VERSION 5.7 ;
  NOWIREEXTENSIONATPIN ON ;
  DIVIDERCHAR "/" ;
  BUSBITCHARS "[]" ;
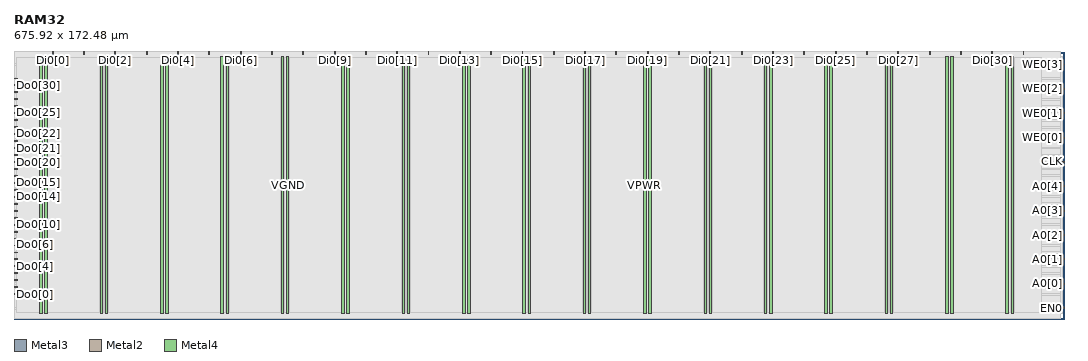
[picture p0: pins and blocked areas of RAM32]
MACRO RAM32
  CLASS BLOCK ;
  FOREIGN RAM32 ;
  ORIGIN 0.000 0.000 ;
  SIZE 675.920 BY 172.480 ;
  PIN A0[0]
    DIRECTION INPUT ;
    USE SIGNAL ;
    ANTENNAGATEAREA 0.726000 ;
    PORT
      LAYER Metal3 ;
        RECT 673.920 22.400 675.920 22.960 ;
    END
  END A0[0]
  PIN A0[1]
    DIRECTION INPUT ;
    USE SIGNAL ;
    ANTENNAGATEAREA 0.726000 ;
    PORT
      LAYER Metal3 ;
        RECT 673.920 38.080 675.920 38.640 ;
    END
  END A0[1]
  PIN A0[2]
    DIRECTION INPUT ;
    USE SIGNAL ;
    ANTENNAGATEAREA 0.726000 ;
    PORT
      LAYER Metal3 ;
        RECT 673.920 53.760 675.920 54.320 ;
    END
  END A0[2]
  PIN A0[3]
    DIRECTION INPUT ;
    USE SIGNAL ;
    ANTENNAGATEAREA 0.726000 ;
    PORT
      LAYER Metal3 ;
        RECT 673.920 69.440 675.920 70.000 ;
    END
  END A0[3]
  PIN A0[4]
    DIRECTION INPUT ;
    USE SIGNAL ;
    ANTENNAGATEAREA 0.726000 ;
    PORT
      LAYER Metal3 ;
        RECT 673.920 85.120 675.920 85.680 ;
    END
  END A0[4]
  PIN CLK
    DIRECTION INPUT ;
    USE SIGNAL ;
    ANTENNAGATEAREA 2.366000 ;
    ANTENNADIFFAREA 0.820800 ;
    PORT
      LAYER Metal3 ;
        RECT 673.920 100.800 675.920 101.360 ;
    END
  END CLK
  PIN Di0[0]
    DIRECTION INPUT ;
    USE SIGNAL ;
    ANTENNAGATEAREA 2.369000 ;
    PORT
      LAYER Metal2 ;
        RECT 24.640 170.480 25.200 172.480 ;
    END
  END Di0[0]
  PIN Di0[10]
    DIRECTION INPUT ;
    USE SIGNAL ;
    ANTENNAGATEAREA 2.369000 ;
    PORT
      LAYER Metal2 ;
        RECT 226.240 170.480 226.800 172.480 ;
    END
  END Di0[10]
  PIN Di0[11]
    DIRECTION INPUT ;
    USE SIGNAL ;
    ANTENNAGATEAREA 2.369000 ;
    PORT
      LAYER Metal2 ;
        RECT 246.400 170.480 246.960 172.480 ;
    END
  END Di0[11]
  PIN Di0[12]
    DIRECTION INPUT ;
    USE SIGNAL ;
    ANTENNAGATEAREA 2.369000 ;
    PORT
      LAYER Metal2 ;
        RECT 266.560 170.480 267.120 172.480 ;
    END
  END Di0[12]
  PIN Di0[13]
    DIRECTION INPUT ;
    USE SIGNAL ;
    ANTENNAGATEAREA 2.369000 ;
    PORT
      LAYER Metal2 ;
        RECT 286.720 170.480 287.280 172.480 ;
    END
  END Di0[13]
  PIN Di0[14]
    DIRECTION INPUT ;
    USE SIGNAL ;
    ANTENNAGATEAREA 2.369000 ;
    PORT
      LAYER Metal2 ;
        RECT 306.880 170.480 307.440 172.480 ;
    END
  END Di0[14]
  PIN Di0[15]
    DIRECTION INPUT ;
    USE SIGNAL ;
    ANTENNAGATEAREA 2.369000 ;
    PORT
      LAYER Metal2 ;
        RECT 327.040 170.480 327.600 172.480 ;
    END
  END Di0[15]
  PIN Di0[16]
    DIRECTION INPUT ;
    USE SIGNAL ;
    ANTENNAGATEAREA 2.369000 ;
    ANTENNADIFFAREA 0.410400 ;
    PORT
      LAYER Metal2 ;
        RECT 347.200 170.480 347.760 172.480 ;
    END
  END Di0[16]
  PIN Di0[17]
    DIRECTION INPUT ;
    USE SIGNAL ;
    ANTENNAGATEAREA 2.369000 ;
    ANTENNADIFFAREA 0.410400 ;
    PORT
      LAYER Metal2 ;
        RECT 367.360 170.480 367.920 172.480 ;
    END
  END Di0[17]
  PIN Di0[18]
    DIRECTION INPUT ;
    USE SIGNAL ;
    ANTENNAGATEAREA 2.369000 ;
    ANTENNADIFFAREA 0.410400 ;
    PORT
      LAYER Metal2 ;
        RECT 387.520 170.480 388.080 172.480 ;
    END
  END Di0[18]
  PIN Di0[19]
    DIRECTION INPUT ;
    USE SIGNAL ;
    ANTENNAGATEAREA 2.369000 ;
    ANTENNADIFFAREA 0.410400 ;
    PORT
      LAYER Metal2 ;
        RECT 407.680 170.480 408.240 172.480 ;
    END
  END Di0[19]
  PIN Di0[1]
    DIRECTION INPUT ;
    USE SIGNAL ;
    ANTENNAGATEAREA 2.369000 ;
    PORT
      LAYER Metal2 ;
        RECT 44.800 170.480 45.360 172.480 ;
    END
  END Di0[1]
  PIN Di0[20]
    DIRECTION INPUT ;
    USE SIGNAL ;
    ANTENNAGATEAREA 2.369000 ;
    ANTENNADIFFAREA 0.410400 ;
    PORT
      LAYER Metal2 ;
        RECT 427.840 170.480 428.400 172.480 ;
    END
  END Di0[20]
  PIN Di0[21]
    DIRECTION INPUT ;
    USE SIGNAL ;
    ANTENNAGATEAREA 2.369000 ;
    ANTENNADIFFAREA 0.410400 ;
    PORT
      LAYER Metal2 ;
        RECT 448.000 170.480 448.560 172.480 ;
    END
  END Di0[21]
  PIN Di0[22]
    DIRECTION INPUT ;
    USE SIGNAL ;
    ANTENNAGATEAREA 2.369000 ;
    ANTENNADIFFAREA 0.410400 ;
    PORT
      LAYER Metal2 ;
        RECT 468.160 170.480 468.720 172.480 ;
    END
  END Di0[22]
  PIN Di0[23]
    DIRECTION INPUT ;
    USE SIGNAL ;
    ANTENNAGATEAREA 2.369000 ;
    ANTENNADIFFAREA 0.410400 ;
    PORT
      LAYER Metal2 ;
        RECT 488.320 170.480 488.880 172.480 ;
    END
  END Di0[23]
  PIN Di0[24]
    DIRECTION INPUT ;
    USE SIGNAL ;
    ANTENNAGATEAREA 2.369000 ;
    ANTENNADIFFAREA 0.410400 ;
    PORT
      LAYER Metal2 ;
        RECT 508.480 170.480 509.040 172.480 ;
    END
  END Di0[24]
  PIN Di0[25]
    DIRECTION INPUT ;
    USE SIGNAL ;
    ANTENNAGATEAREA 2.369000 ;
    ANTENNADIFFAREA 0.410400 ;
    PORT
      LAYER Metal2 ;
        RECT 528.640 170.480 529.200 172.480 ;
    END
  END Di0[25]
  PIN Di0[26]
    DIRECTION INPUT ;
    USE SIGNAL ;
    ANTENNAGATEAREA 2.369000 ;
    ANTENNADIFFAREA 0.410400 ;
    PORT
      LAYER Metal2 ;
        RECT 548.800 170.480 549.360 172.480 ;
    END
  END Di0[26]
  PIN Di0[27]
    DIRECTION INPUT ;
    USE SIGNAL ;
    ANTENNAGATEAREA 2.369000 ;
    ANTENNADIFFAREA 0.410400 ;
    PORT
      LAYER Metal2 ;
        RECT 568.960 170.480 569.520 172.480 ;
    END
  END Di0[27]
  PIN Di0[28]
    DIRECTION INPUT ;
    USE SIGNAL ;
    ANTENNAGATEAREA 2.369000 ;
    ANTENNADIFFAREA 0.410400 ;
    PORT
      LAYER Metal2 ;
        RECT 589.120 170.480 589.680 172.480 ;
    END
  END Di0[28]
  PIN Di0[29]
    DIRECTION INPUT ;
    USE SIGNAL ;
    ANTENNAGATEAREA 2.369000 ;
    ANTENNADIFFAREA 0.410400 ;
    PORT
      LAYER Metal2 ;
        RECT 609.280 170.480 609.840 172.480 ;
    END
  END Di0[29]
  PIN Di0[2]
    DIRECTION INPUT ;
    USE SIGNAL ;
    ANTENNAGATEAREA 2.369000 ;
    PORT
      LAYER Metal2 ;
        RECT 64.960 170.480 65.520 172.480 ;
    END
  END Di0[2]
  PIN Di0[30]
    DIRECTION INPUT ;
    USE SIGNAL ;
    ANTENNAGATEAREA 2.369000 ;
    ANTENNADIFFAREA 0.410400 ;
    PORT
      LAYER Metal2 ;
        RECT 629.440 170.480 630.000 172.480 ;
    END
  END Di0[30]
  PIN Di0[31]
    DIRECTION INPUT ;
    USE SIGNAL ;
    ANTENNAGATEAREA 2.369000 ;
    ANTENNADIFFAREA 0.410400 ;
    PORT
      LAYER Metal2 ;
        RECT 649.600 170.480 650.160 172.480 ;
    END
  END Di0[31]
  PIN Di0[3]
    DIRECTION INPUT ;
    USE SIGNAL ;
    ANTENNAGATEAREA 2.369000 ;
    PORT
      LAYER Metal2 ;
        RECT 85.120 170.480 85.680 172.480 ;
    END
  END Di0[3]
  PIN Di0[4]
    DIRECTION INPUT ;
    USE SIGNAL ;
    ANTENNAGATEAREA 2.369000 ;
    PORT
      LAYER Metal2 ;
        RECT 105.280 170.480 105.840 172.480 ;
    END
  END Di0[4]
  PIN Di0[5]
    DIRECTION INPUT ;
    USE SIGNAL ;
    ANTENNAGATEAREA 2.369000 ;
    PORT
      LAYER Metal2 ;
        RECT 125.440 170.480 126.000 172.480 ;
    END
  END Di0[5]
  PIN Di0[6]
    DIRECTION INPUT ;
    USE SIGNAL ;
    ANTENNAGATEAREA 2.369000 ;
    PORT
      LAYER Metal2 ;
        RECT 145.600 170.480 146.160 172.480 ;
    END
  END Di0[6]
  PIN Di0[7]
    DIRECTION INPUT ;
    USE SIGNAL ;
    ANTENNAGATEAREA 2.369000 ;
    PORT
      LAYER Metal2 ;
        RECT 165.760 170.480 166.320 172.480 ;
    END
  END Di0[7]
  PIN Di0[8]
    DIRECTION INPUT ;
    USE SIGNAL ;
    ANTENNAGATEAREA 2.369000 ;
    PORT
      LAYER Metal2 ;
        RECT 185.920 170.480 186.480 172.480 ;
    END
  END Di0[8]
  PIN Di0[9]
    DIRECTION INPUT ;
    USE SIGNAL ;
    ANTENNAGATEAREA 2.369000 ;
    PORT
      LAYER Metal2 ;
        RECT 206.080 170.480 206.640 172.480 ;
    END
  END Di0[9]
  PIN Do0[0]
    DIRECTION OUTPUT ;
    USE SIGNAL ;
    ANTENNADIFFAREA 0.897600 ;
    PORT
      LAYER Metal3 ;
        RECT 0.000 15.680 2.000 16.240 ;
    END
  END Do0[0]
  PIN Do0[10]
    DIRECTION OUTPUT ;
    USE SIGNAL ;
    ANTENNADIFFAREA 0.897600 ;
    PORT
      LAYER Metal3 ;
        RECT 0.000 60.480 2.000 61.040 ;
    END
  END Do0[10]
  PIN Do0[11]
    DIRECTION OUTPUT ;
    USE SIGNAL ;
    ANTENNADIFFAREA 0.897600 ;
    PORT
      LAYER Metal3 ;
        RECT 0.000 64.960 2.000 65.520 ;
    END
  END Do0[11]
  PIN Do0[12]
    DIRECTION OUTPUT ;
    USE SIGNAL ;
    ANTENNADIFFAREA 0.897600 ;
    PORT
      LAYER Metal3 ;
        RECT 0.000 69.440 2.000 70.000 ;
    END
  END Do0[12]
  PIN Do0[13]
    DIRECTION OUTPUT ;
    USE SIGNAL ;
    ANTENNADIFFAREA 0.897600 ;
    PORT
      LAYER Metal3 ;
        RECT 0.000 73.920 2.000 74.480 ;
    END
  END Do0[13]
  PIN Do0[14]
    DIRECTION OUTPUT ;
    USE SIGNAL ;
    ANTENNADIFFAREA 0.897600 ;
    PORT
      LAYER Metal3 ;
        RECT 0.000 78.400 2.000 78.960 ;
    END
  END Do0[14]
  PIN Do0[15]
    DIRECTION OUTPUT ;
    USE SIGNAL ;
    ANTENNADIFFAREA 0.897600 ;
    PORT
      LAYER Metal3 ;
        RECT 0.000 82.880 2.000 83.440 ;
    END
  END Do0[15]
  PIN Do0[16]
    DIRECTION OUTPUT ;
    USE SIGNAL ;
    ANTENNADIFFAREA 0.897600 ;
    PORT
      LAYER Metal3 ;
        RECT 0.000 87.360 2.000 87.920 ;
    END
  END Do0[16]
  PIN Do0[17]
    DIRECTION OUTPUT ;
    USE SIGNAL ;
    ANTENNADIFFAREA 0.897600 ;
    PORT
      LAYER Metal3 ;
        RECT 0.000 91.840 2.000 92.400 ;
    END
  END Do0[17]
  PIN Do0[18]
    DIRECTION OUTPUT ;
    USE SIGNAL ;
    ANTENNADIFFAREA 0.897600 ;
    PORT
      LAYER Metal3 ;
        RECT 0.000 96.320 2.000 96.880 ;
    END
  END Do0[18]
  PIN Do0[19]
    DIRECTION OUTPUT ;
    USE SIGNAL ;
    ANTENNADIFFAREA 0.897600 ;
    PORT
      LAYER Metal3 ;
        RECT 0.000 100.800 2.000 101.360 ;
    END
  END Do0[19]
  PIN Do0[1]
    DIRECTION OUTPUT ;
    USE SIGNAL ;
    ANTENNADIFFAREA 0.897600 ;
    PORT
      LAYER Metal3 ;
        RECT 0.000 20.160 2.000 20.720 ;
    END
  END Do0[1]
  PIN Do0[20]
    DIRECTION OUTPUT ;
    USE SIGNAL ;
    ANTENNADIFFAREA 0.897600 ;
    PORT
      LAYER Metal3 ;
        RECT 0.000 105.280 2.000 105.840 ;
    END
  END Do0[20]
  PIN Do0[21]
    DIRECTION OUTPUT ;
    USE SIGNAL ;
    ANTENNADIFFAREA 0.897600 ;
    PORT
      LAYER Metal3 ;
        RECT 0.000 109.760 2.000 110.320 ;
    END
  END Do0[21]
  PIN Do0[22]
    DIRECTION OUTPUT ;
    USE SIGNAL ;
    ANTENNADIFFAREA 0.897600 ;
    PORT
      LAYER Metal3 ;
        RECT 0.000 114.240 2.000 114.800 ;
    END
  END Do0[22]
  PIN Do0[23]
    DIRECTION OUTPUT ;
    USE SIGNAL ;
    ANTENNADIFFAREA 0.897600 ;
    PORT
      LAYER Metal3 ;
        RECT 0.000 118.720 2.000 119.280 ;
    END
  END Do0[23]
  PIN Do0[24]
    DIRECTION OUTPUT ;
    USE SIGNAL ;
    ANTENNADIFFAREA 1.308000 ;
    PORT
      LAYER Metal3 ;
        RECT 0.000 123.200 2.000 123.760 ;
    END
  END Do0[24]
  PIN Do0[25]
    DIRECTION OUTPUT ;
    USE SIGNAL ;
    ANTENNADIFFAREA 1.308000 ;
    PORT
      LAYER Metal3 ;
        RECT 0.000 127.680 2.000 128.240 ;
    END
  END Do0[25]
  PIN Do0[26]
    DIRECTION OUTPUT ;
    USE SIGNAL ;
    ANTENNADIFFAREA 1.308000 ;
    PORT
      LAYER Metal3 ;
        RECT 0.000 132.160 2.000 132.720 ;
    END
  END Do0[26]
  PIN Do0[27]
    DIRECTION OUTPUT ;
    USE SIGNAL ;
    ANTENNADIFFAREA 1.308000 ;
    PORT
      LAYER Metal3 ;
        RECT 0.000 136.640 2.000 137.200 ;
    END
  END Do0[27]
  PIN Do0[28]
    DIRECTION OUTPUT ;
    USE SIGNAL ;
    ANTENNADIFFAREA 1.308000 ;
    PORT
      LAYER Metal3 ;
        RECT 0.000 141.120 2.000 141.680 ;
    END
  END Do0[28]
  PIN Do0[29]
    DIRECTION OUTPUT ;
    USE SIGNAL ;
    ANTENNADIFFAREA 1.308000 ;
    PORT
      LAYER Metal3 ;
        RECT 0.000 145.600 2.000 146.160 ;
    END
  END Do0[29]
  PIN Do0[2]
    DIRECTION OUTPUT ;
    USE SIGNAL ;
    ANTENNADIFFAREA 0.897600 ;
    PORT
      LAYER Metal3 ;
        RECT 0.000 24.640 2.000 25.200 ;
    END
  END Do0[2]
  PIN Do0[30]
    DIRECTION OUTPUT ;
    USE SIGNAL ;
    ANTENNADIFFAREA 1.308000 ;
    PORT
      LAYER Metal3 ;
        RECT 0.000 150.080 2.000 150.640 ;
    END
  END Do0[30]
  PIN Do0[31]
    DIRECTION OUTPUT ;
    USE SIGNAL ;
    ANTENNADIFFAREA 1.308000 ;
    PORT
      LAYER Metal3 ;
        RECT 0.000 154.560 2.000 155.120 ;
    END
  END Do0[31]
  PIN Do0[3]
    DIRECTION OUTPUT ;
    USE SIGNAL ;
    ANTENNADIFFAREA 0.897600 ;
    PORT
      LAYER Metal3 ;
        RECT 0.000 29.120 2.000 29.680 ;
    END
  END Do0[3]
  PIN Do0[4]
    DIRECTION OUTPUT ;
    USE SIGNAL ;
    ANTENNADIFFAREA 0.897600 ;
    PORT
      LAYER Metal3 ;
        RECT 0.000 33.600 2.000 34.160 ;
    END
  END Do0[4]
  PIN Do0[5]
    DIRECTION OUTPUT ;
    USE SIGNAL ;
    ANTENNADIFFAREA 0.897600 ;
    PORT
      LAYER Metal3 ;
        RECT 0.000 38.080 2.000 38.640 ;
    END
  END Do0[5]
  PIN Do0[6]
    DIRECTION OUTPUT ;
    USE SIGNAL ;
    ANTENNADIFFAREA 0.897600 ;
    PORT
      LAYER Metal3 ;
        RECT 0.000 42.560 2.000 43.120 ;
    END
  END Do0[6]
  PIN Do0[7]
    DIRECTION OUTPUT ;
    USE SIGNAL ;
    ANTENNADIFFAREA 0.897600 ;
    PORT
      LAYER Metal3 ;
        RECT 0.000 47.040 2.000 47.600 ;
    END
  END Do0[7]
  PIN Do0[8]
    DIRECTION OUTPUT ;
    USE SIGNAL ;
    ANTENNADIFFAREA 0.897600 ;
    PORT
      LAYER Metal3 ;
        RECT 0.000 51.520 2.000 52.080 ;
    END
  END Do0[8]
  PIN Do0[9]
    DIRECTION OUTPUT ;
    USE SIGNAL ;
    ANTENNADIFFAREA 0.897600 ;
    PORT
      LAYER Metal3 ;
        RECT 0.000 56.000 2.000 56.560 ;
    END
  END Do0[9]
  PIN EN0
    DIRECTION INPUT ;
    USE SIGNAL ;
    ANTENNAGATEAREA 0.726000 ;
    PORT
      LAYER Metal3 ;
        RECT 673.920 6.720 675.920 7.280 ;
    END
  END EN0
  PIN VGND
    DIRECTION INOUT ;
    USE GROUND ;
    PORT
      LAYER Metal4 ;
        RECT 19.940 3.620 21.540 168.860 ;
    END
    PORT
      LAYER Metal4 ;
        RECT 58.810 3.620 60.410 168.860 ;
    END
    PORT
      LAYER Metal4 ;
        RECT 97.680 3.620 99.280 168.860 ;
    END
    PORT
      LAYER Metal4 ;
        RECT 136.550 3.620 138.150 168.860 ;
    END
    PORT
      LAYER Metal4 ;
        RECT 175.420 3.620 177.020 168.860 ;
    END
    PORT
      LAYER Metal4 ;
        RECT 214.290 3.620 215.890 168.860 ;
    END
    PORT
      LAYER Metal4 ;
        RECT 253.160 3.620 254.760 168.860 ;
    END
    PORT
      LAYER Metal4 ;
        RECT 292.030 3.620 293.630 168.860 ;
    END
    PORT
      LAYER Metal4 ;
        RECT 330.900 3.620 332.500 168.860 ;
    END
    PORT
      LAYER Metal4 ;
        RECT 369.770 3.620 371.370 168.860 ;
    END
    PORT
      LAYER Metal4 ;
        RECT 408.640 3.620 410.240 168.860 ;
    END
    PORT
      LAYER Metal4 ;
        RECT 447.510 3.620 449.110 168.860 ;
    END
    PORT
      LAYER Metal4 ;
        RECT 486.380 3.620 487.980 168.860 ;
    END
    PORT
      LAYER Metal4 ;
        RECT 525.250 3.620 526.850 168.860 ;
    END
    PORT
      LAYER Metal4 ;
        RECT 564.120 3.620 565.720 168.860 ;
    END
    PORT
      LAYER Metal4 ;
        RECT 602.990 3.620 604.590 168.860 ;
    END
    PORT
      LAYER Metal4 ;
        RECT 641.860 3.620 643.460 168.860 ;
    END
  END VGND
  PIN VPWR
    DIRECTION INOUT ;
    USE POWER ;
    PORT
      LAYER Metal4 ;
        RECT 16.640 3.620 18.240 168.860 ;
    END
    PORT
      LAYER Metal4 ;
        RECT 55.510 3.620 57.110 168.860 ;
    END
    PORT
      LAYER Metal4 ;
        RECT 94.380 3.620 95.980 168.860 ;
    END
    PORT
      LAYER Metal4 ;
        RECT 133.250 3.620 134.850 168.860 ;
    END
    PORT
      LAYER Metal4 ;
        RECT 172.120 3.620 173.720 168.860 ;
    END
    PORT
      LAYER Metal4 ;
        RECT 210.990 3.620 212.590 168.860 ;
    END
    PORT
      LAYER Metal4 ;
        RECT 249.860 3.620 251.460 168.860 ;
    END
    PORT
      LAYER Metal4 ;
        RECT 288.730 3.620 290.330 168.860 ;
    END
    PORT
      LAYER Metal4 ;
        RECT 327.600 3.620 329.200 168.860 ;
    END
    PORT
      LAYER Metal4 ;
        RECT 366.470 3.620 368.070 168.860 ;
    END
    PORT
      LAYER Metal4 ;
        RECT 405.340 3.620 406.940 168.860 ;
    END
    PORT
      LAYER Metal4 ;
        RECT 444.210 3.620 445.810 168.860 ;
    END
    PORT
      LAYER Metal4 ;
        RECT 483.080 3.620 484.680 168.860 ;
    END
    PORT
      LAYER Metal4 ;
        RECT 521.950 3.620 523.550 168.860 ;
    END
    PORT
      LAYER Metal4 ;
        RECT 560.820 3.620 562.420 168.860 ;
    END
    PORT
      LAYER Metal4 ;
        RECT 599.690 3.620 601.290 168.860 ;
    END
    PORT
      LAYER Metal4 ;
        RECT 638.560 3.620 640.160 168.860 ;
    END
  END VPWR
  PIN WE0[0]
    DIRECTION INPUT ;
    USE SIGNAL ;
    ANTENNAGATEAREA 0.726000 ;
    PORT
      LAYER Metal3 ;
        RECT 673.920 116.480 675.920 117.040 ;
    END
  END WE0[0]
  PIN WE0[1]
    DIRECTION INPUT ;
    USE SIGNAL ;
    ANTENNAGATEAREA 0.726000 ;
    PORT
      LAYER Metal3 ;
        RECT 673.920 132.160 675.920 132.720 ;
    END
  END WE0[1]
  PIN WE0[2]
    DIRECTION INPUT ;
    USE SIGNAL ;
    ANTENNAGATEAREA 0.726000 ;
    PORT
      LAYER Metal3 ;
        RECT 673.920 147.840 675.920 148.400 ;
    END
  END WE0[2]
  PIN WE0[3]
    DIRECTION INPUT ;
    USE SIGNAL ;
    ANTENNAGATEAREA 0.726000 ;
    PORT
      LAYER Metal3 ;
        RECT 673.920 163.520 675.920 164.080 ;
    END
  END WE0[3]
  OBS
      LAYER Nwell ;
        RECT 0.690 3.490 675.230 168.990 ;
      LAYER Metal1 ;
        RECT 1.120 3.620 674.800 168.860 ;
      LAYER Metal2 ;
        RECT 0.140 170.180 24.340 172.390 ;
        RECT 25.500 170.180 44.500 172.390 ;
        RECT 45.660 170.180 64.660 172.390 ;
        RECT 65.820 170.180 84.820 172.390 ;
        RECT 85.980 170.180 104.980 172.390 ;
        RECT 106.140 170.180 125.140 172.390 ;
        RECT 126.300 170.180 145.300 172.390 ;
        RECT 146.460 170.180 165.460 172.390 ;
        RECT 166.620 170.180 185.620 172.390 ;
        RECT 186.780 170.180 205.780 172.390 ;
        RECT 206.940 170.180 225.940 172.390 ;
        RECT 227.100 170.180 246.100 172.390 ;
        RECT 247.260 170.180 266.260 172.390 ;
        RECT 267.420 170.180 286.420 172.390 ;
        RECT 287.580 170.180 306.580 172.390 ;
        RECT 307.740 170.180 326.740 172.390 ;
        RECT 327.900 170.180 346.900 172.390 ;
        RECT 348.060 170.180 367.060 172.390 ;
        RECT 368.220 170.180 387.220 172.390 ;
        RECT 388.380 170.180 407.380 172.390 ;
        RECT 408.540 170.180 427.540 172.390 ;
        RECT 428.700 170.180 447.700 172.390 ;
        RECT 448.860 170.180 467.860 172.390 ;
        RECT 469.020 170.180 488.020 172.390 ;
        RECT 489.180 170.180 508.180 172.390 ;
        RECT 509.340 170.180 528.340 172.390 ;
        RECT 529.500 170.180 548.500 172.390 ;
        RECT 549.660 170.180 568.660 172.390 ;
        RECT 569.820 170.180 588.820 172.390 ;
        RECT 589.980 170.180 608.980 172.390 ;
        RECT 610.140 170.180 629.140 172.390 ;
        RECT 630.300 170.180 649.300 172.390 ;
        RECT 650.460 170.180 666.820 172.390 ;
        RECT 0.140 0.090 666.820 170.180 ;
      LAYER Metal3 ;
        RECT 0.090 164.380 673.920 172.340 ;
        RECT 0.090 163.220 673.620 164.380 ;
        RECT 0.090 155.420 673.920 163.220 ;
        RECT 2.300 154.260 673.920 155.420 ;
        RECT 0.090 150.940 673.920 154.260 ;
        RECT 2.300 149.780 673.920 150.940 ;
        RECT 0.090 148.700 673.920 149.780 ;
        RECT 0.090 147.540 673.620 148.700 ;
        RECT 0.090 146.460 673.920 147.540 ;
        RECT 2.300 145.300 673.920 146.460 ;
        RECT 0.090 141.980 673.920 145.300 ;
        RECT 2.300 140.820 673.920 141.980 ;
        RECT 0.090 137.500 673.920 140.820 ;
        RECT 2.300 136.340 673.920 137.500 ;
        RECT 0.090 133.020 673.920 136.340 ;
        RECT 2.300 131.860 673.620 133.020 ;
        RECT 0.090 128.540 673.920 131.860 ;
        RECT 2.300 127.380 673.920 128.540 ;
        RECT 0.090 124.060 673.920 127.380 ;
        RECT 2.300 122.900 673.920 124.060 ;
        RECT 0.090 119.580 673.920 122.900 ;
        RECT 2.300 118.420 673.920 119.580 ;
        RECT 0.090 117.340 673.920 118.420 ;
        RECT 0.090 116.180 673.620 117.340 ;
        RECT 0.090 115.100 673.920 116.180 ;
        RECT 2.300 113.940 673.920 115.100 ;
        RECT 0.090 110.620 673.920 113.940 ;
        RECT 2.300 109.460 673.920 110.620 ;
        RECT 0.090 106.140 673.920 109.460 ;
        RECT 2.300 104.980 673.920 106.140 ;
        RECT 0.090 101.660 673.920 104.980 ;
        RECT 2.300 100.500 673.620 101.660 ;
        RECT 0.090 97.180 673.920 100.500 ;
        RECT 2.300 96.020 673.920 97.180 ;
        RECT 0.090 92.700 673.920 96.020 ;
        RECT 2.300 91.540 673.920 92.700 ;
        RECT 0.090 88.220 673.920 91.540 ;
        RECT 2.300 87.060 673.920 88.220 ;
        RECT 0.090 85.980 673.920 87.060 ;
        RECT 0.090 84.820 673.620 85.980 ;
        RECT 0.090 83.740 673.920 84.820 ;
        RECT 2.300 82.580 673.920 83.740 ;
        RECT 0.090 79.260 673.920 82.580 ;
        RECT 2.300 78.100 673.920 79.260 ;
        RECT 0.090 74.780 673.920 78.100 ;
        RECT 2.300 73.620 673.920 74.780 ;
        RECT 0.090 70.300 673.920 73.620 ;
        RECT 2.300 69.140 673.620 70.300 ;
        RECT 0.090 65.820 673.920 69.140 ;
        RECT 2.300 64.660 673.920 65.820 ;
        RECT 0.090 61.340 673.920 64.660 ;
        RECT 2.300 60.180 673.920 61.340 ;
        RECT 0.090 56.860 673.920 60.180 ;
        RECT 2.300 55.700 673.920 56.860 ;
        RECT 0.090 54.620 673.920 55.700 ;
        RECT 0.090 53.460 673.620 54.620 ;
        RECT 0.090 52.380 673.920 53.460 ;
        RECT 2.300 51.220 673.920 52.380 ;
        RECT 0.090 47.900 673.920 51.220 ;
        RECT 2.300 46.740 673.920 47.900 ;
        RECT 0.090 43.420 673.920 46.740 ;
        RECT 2.300 42.260 673.920 43.420 ;
        RECT 0.090 38.940 673.920 42.260 ;
        RECT 2.300 37.780 673.620 38.940 ;
        RECT 0.090 34.460 673.920 37.780 ;
        RECT 2.300 33.300 673.920 34.460 ;
        RECT 0.090 29.980 673.920 33.300 ;
        RECT 2.300 28.820 673.920 29.980 ;
        RECT 0.090 25.500 673.920 28.820 ;
        RECT 2.300 24.340 673.920 25.500 ;
        RECT 0.090 23.260 673.920 24.340 ;
        RECT 0.090 22.100 673.620 23.260 ;
        RECT 0.090 21.020 673.920 22.100 ;
        RECT 2.300 19.860 673.920 21.020 ;
        RECT 0.090 16.540 673.920 19.860 ;
        RECT 2.300 15.380 673.920 16.540 ;
        RECT 0.090 7.580 673.920 15.380 ;
        RECT 0.090 6.420 673.620 7.580 ;
        RECT 0.090 0.140 673.920 6.420 ;
      LAYER Metal4 ;
        RECT 1.820 4.010 16.340 168.470 ;
        RECT 18.540 4.010 19.640 168.470 ;
        RECT 21.840 4.010 55.210 168.470 ;
        RECT 57.410 4.010 58.510 168.470 ;
        RECT 60.710 4.010 94.080 168.470 ;
        RECT 96.280 4.010 97.380 168.470 ;
        RECT 99.580 4.010 132.950 168.470 ;
        RECT 135.150 4.010 136.250 168.470 ;
        RECT 138.450 4.010 171.820 168.470 ;
        RECT 174.020 4.010 175.120 168.470 ;
        RECT 177.320 4.010 210.690 168.470 ;
        RECT 212.890 4.010 213.990 168.470 ;
        RECT 216.190 4.010 249.560 168.470 ;
        RECT 251.760 4.010 252.860 168.470 ;
        RECT 255.060 4.010 288.430 168.470 ;
        RECT 290.630 4.010 291.730 168.470 ;
        RECT 293.930 4.010 327.300 168.470 ;
        RECT 329.500 4.010 330.600 168.470 ;
        RECT 332.800 4.010 366.170 168.470 ;
        RECT 368.370 4.010 369.470 168.470 ;
        RECT 371.670 4.010 405.040 168.470 ;
        RECT 407.240 4.010 408.340 168.470 ;
        RECT 410.540 4.010 443.910 168.470 ;
        RECT 446.110 4.010 447.210 168.470 ;
        RECT 449.410 4.010 482.780 168.470 ;
        RECT 484.980 4.010 486.080 168.470 ;
        RECT 488.280 4.010 521.650 168.470 ;
        RECT 523.850 4.010 524.950 168.470 ;
        RECT 527.150 4.010 560.520 168.470 ;
        RECT 562.720 4.010 563.820 168.470 ;
        RECT 566.020 4.010 599.390 168.470 ;
        RECT 601.590 4.010 602.690 168.470 ;
        RECT 604.890 4.010 638.260 168.470 ;
        RECT 640.460 4.010 641.560 168.470 ;
        RECT 643.760 4.010 661.220 168.470 ;
  END
END RAM32
END LIBRARY

